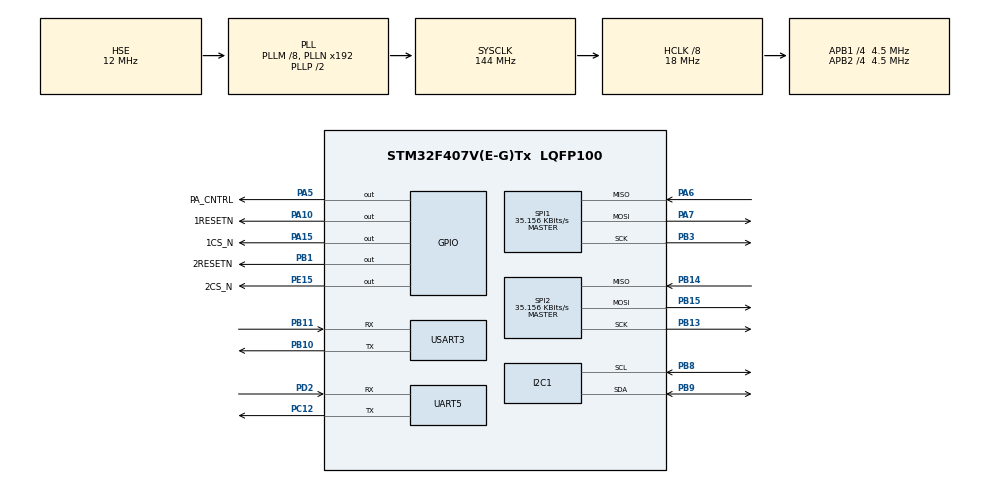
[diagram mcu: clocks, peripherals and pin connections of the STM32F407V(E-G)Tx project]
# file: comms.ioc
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Mcu.Family=STM32F4
Mcu.Name=STM32F407V(E-G)Tx
Mcu.Package=LQFP100
NVIC.PriorityGroup=NVIC_PRIORITYGROUP_4
PA10.GPIO_Label=1RESETN
PA10.PinState=GPIO_PIN_SET
PA10.Signal=GPIO_Output
PA15.GPIO_Label=1CS_N
PA15.PinState=GPIO_PIN_SET
PA15.Signal=GPIO_Output
PA5.GPIO_Label=PA_CNTRL
PA5.Signal=GPIO_Output
PA6.GPIO_Speed=GPIO_SPEED_FREQ_LOW
PA6.Mode=Full_Duplex_Master
PA6.Signal=SPI1_MISO
PA7.GPIO_Speed=GPIO_SPEED_FREQ_LOW
PA7.Mode=Full_Duplex_Master
PA7.Signal=SPI1_MOSI
PB1.GPIO_Label=2RESETN
PB1.PinState=GPIO_PIN_SET
PB1.Signal=GPIO_Output
PB10.Mode=Asynchronous
PB10.Signal=USART3_TX
PB11.Mode=Asynchronous
PB11.Signal=USART3_RX
PB13.GPIO_Speed=GPIO_SPEED_FREQ_LOW
PB13.Mode=Full_Duplex_Master
PB13.Signal=SPI2_SCK
PB14.GPIO_Speed=GPIO_SPEED_FREQ_LOW
PB14.Mode=Full_Duplex_Master
PB14.Signal=SPI2_MISO
PB15.GPIO_Speed=GPIO_SPEED_FREQ_LOW
PB15.Mode=Full_Duplex_Master
PB15.Signal=SPI2_MOSI
PB3.GPIO_Speed=GPIO_SPEED_FREQ_LOW
PB3.Mode=Full_Duplex_Master
PB3.Signal=SPI1_SCK
PB8.Mode=I2C
PB8.Signal=I2C1_SCL
PB9.Mode=I2C
PB9.Signal=I2C1_SDA
PC12.Mode=Asynchronous
PC12.Signal=UART5_TX
PD2.Mode=Asynchronous
PD2.Signal=UART5_RX
PE15.GPIO_Label=2CS_N
PE15.PinState=GPIO_PIN_SET
PE15.Signal=GPIO_Output
PH0-OSC_IN.Mode=HSE-External-Oscillator
PH0-OSC_IN.Signal=RCC_OSC_IN
PH1-OSC_OUT.Mode=HSE-External-Oscillator
PH1-OSC_OUT.Signal=RCC_OSC_OUT
ProjectManager.HeapSize=0x200
ProjectManager.StackSize=0x400
ProjectManager.TargetToolchain=SW4STM32
RCC.48MHZClocksFreq_Value=72000000
RCC.AHBCLKDivider=RCC_SYSCLK_DIV8
RCC.AHBFreq_Value=18000000
RCC.APB1CLKDivider=RCC_HCLK_DIV4
RCC.APB1Freq_Value=4500000
RCC.APB1TimFreq_Value=9000000
RCC.APB2CLKDivider=RCC_HCLK_DIV4
RCC.APB2Freq_Value=4500000
RCC.APB2TimFreq_Value=9000000
RCC.CortexFreq_Value=18000000
RCC.HCLKFreq_Value=18000000
RCC.HSE_VALUE=12000000
RCC.HSI_VALUE=16000000
RCC.LSE_VALUE=32768
RCC.PLLM=8
RCC.PLLSourceVirtual=RCC_PLLSOURCE_HSE
RCC.SYSCLKFreq_VALUE=144000000
RCC.SYSCLKSource=RCC_SYSCLKSOURCE_PLLCLK
RCC.VCOOutputFreq_Value=288000000
SPI1.BaudRatePrescaler=SPI_BAUDRATEPRESCALER_128
SPI1.CalculateBaudRate=35.156 KBits/s
SPI1.Mode=SPI_MODE_MASTER
SPI2.BaudRatePrescaler=SPI_BAUDRATEPRESCALER_128
SPI2.CalculateBaudRate=35.156 KBits/s
SPI2.Mode=SPI_MODE_MASTER
board=comms

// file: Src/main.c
/**
  ******************************************************************************
  * File Name          : main.c
  * Description        : Main program body
  ******************************************************************************
  *
  * COPYRIGHT(c) 2016 STMicroelectronics
  *
  * Redistribution and use in source and binary forms, with or without modification,
  * are permitted provided that the following conditions are met:
  *   1. Redistributions of source code must retain the above copyright notice,
  *      this list of conditions and the following disclaimer.
  *   2. Redistributions in binary form must reproduce the above copyright notice,
  *      this list of conditions and the following disclaimer in the documentation
  *      and/or other materials provided with the distribution.
  *   3. Neither the name of STMicroelectronics nor the names of its contributors
  *      may be used to endorse or promote products derived from this software
  *      without specific prior written permission.
  *
  * THIS SOFTWARE IS PROVIDED BY THE COPYRIGHT HOLDERS AND CONTRIBUTORS "AS IS"
  * AND ANY EXPRESS OR IMPLIED WARRANTIES, INCLUDING, BUT NOT LIMITED TO, THE
  * IMPLIED WARRANTIES OF MERCHANTABILITY AND FITNESS FOR A PARTICULAR PURPOSE ARE
  * DISCLAIMED. IN NO EVENT SHALL THE COPYRIGHT HOLDER OR CONTRIBUTORS BE LIABLE
  * FOR ANY DIRECT, INDIRECT, INCIDENTAL, SPECIAL, EXEMPLARY, OR CONSEQUENTIAL
  * DAMAGES (INCLUDING, BUT NOT LIMITED TO, PROCUREMENT OF SUBSTITUTE GOODS OR
  * SERVICES; LOSS OF USE, DATA, OR PROFITS; OR BUSINESS INTERRUPTION) HOWEVER
  * CAUSED AND ON ANY THEORY OF LIABILITY, WHETHER IN CONTRACT, STRICT LIABILITY,
  * OR TORT (INCLUDING NEGLIGENCE OR OTHERWISE) ARISING IN ANY WAY OUT OF THE USE
  * OF THIS SOFTWARE, EVEN IF ADVISED OF THE POSSIBILITY OF SUCH DAMAGE.
  *
  ******************************************************************************
  */
#include "stm32f4xx_hal.h"

/* USER CODE BEGIN Includes */
#include "../../../../cc1120/cc_definitions.h"
#include "../../../../cc1120/cc_Tx_Init.h"
#include "../../../../cc1120/cc112x_spi.h"
/* USER CODE END Includes */

I2C_HandleTypeDef hi2c1;

SPI_HandleTypeDef hspi1;
SPI_HandleTypeDef hspi2;

UART_HandleTypeDef huart5;
UART_HandleTypeDef huart3;

/* USER CODE BEGIN PV */
/* Private variables ---------------------------------------------------------*/

/* USER CODE END PV */

void SystemClock_Config(void);
static void MX_GPIO_Init(void);
static void MX_I2C1_Init(void);
static void MX_SPI1_Init(void);
static void MX_SPI2_Init(void);
static void MX_UART5_Init(void);
static void MX_USART3_UART_Init(void);

/* USER CODE BEGIN PFP */
/* Private function prototypes -----------------------------------------------*/

/* USER CODE END PFP */

int main(void)
{

  /* MCU Configuration----------------------------------------------------------*/

  /* Reset of all peripherals, Initializes the Flash interface and the Systick. */
  HAL_Init();

  /* Configure the system clock */
  SystemClock_Config();

  /* Initialize all configured peripherals */
  MX_GPIO_Init();
  MX_I2C1_Init();
  MX_SPI1_Init();
  MX_SPI2_Init();
  MX_UART5_Init();
  MX_USART3_UART_Init();

  /* USER CODE BEGIN 2 */
  cc_Tx_INIT();
  /* USER CODE END 2 */

  /* Infinite loop */
  while (1)
  {

  }

}

/** System Clock Configuration
*/
void SystemClock_Config(void)
{

  RCC_OscInitTypeDef RCC_OscInitStruct;
  RCC_ClkInitTypeDef RCC_ClkInitStruct;

  __HAL_RCC_PWR_CLK_ENABLE();

  __HAL_PWR_VOLTAGESCALING_CONFIG(PWR_REGULATOR_VOLTAGE_SCALE1);

  RCC_OscInitStruct.OscillatorType = RCC_OSCILLATORTYPE_HSE;
  RCC_OscInitStruct.HSEState = RCC_HSE_ON;
  RCC_OscInitStruct.PLL.PLLState = RCC_PLL_ON;
  RCC_OscInitStruct.PLL.PLLSource = RCC_PLLSOURCE_HSE;
  RCC_OscInitStruct.PLL.PLLM = 8;
  RCC_OscInitStruct.PLL.PLLN = 192;
  RCC_OscInitStruct.PLL.PLLP = RCC_PLLP_DIV2;
  RCC_OscInitStruct.PLL.PLLQ = 4;
  HAL_RCC_OscConfig(&RCC_OscInitStruct);

  RCC_ClkInitStruct.ClockType = RCC_CLOCKTYPE_HCLK|RCC_CLOCKTYPE_SYSCLK
                              |RCC_CLOCKTYPE_PCLK1|RCC_CLOCKTYPE_PCLK2;
  RCC_ClkInitStruct.SYSCLKSource = RCC_SYSCLKSOURCE_PLLCLK;
  RCC_ClkInitStruct.AHBCLKDivider = RCC_SYSCLK_DIV8;
  RCC_ClkInitStruct.APB1CLKDivider = RCC_HCLK_DIV4;
  RCC_ClkInitStruct.APB2CLKDivider = RCC_HCLK_DIV4;
  HAL_RCC_ClockConfig(&RCC_ClkInitStruct, FLASH_LATENCY_0);

  HAL_SYSTICK_Config(HAL_RCC_GetHCLKFreq()/1000);

  HAL_SYSTICK_CLKSourceConfig(SYSTICK_CLKSOURCE_HCLK);

  /* SysTick_IRQn interrupt configuration */
  HAL_NVIC_SetPriority(SysTick_IRQn, 0, 0);
}

/* I2C1 init function */
void MX_I2C1_Init(void)
{

  hi2c1.Instance = I2C1;
  hi2c1.Init.ClockSpeed = 100000;
  hi2c1.Init.DutyCycle = I2C_DUTYCYCLE_2;
  hi2c1.Init.OwnAddress1 = 0;
  hi2c1.Init.AddressingMode = I2C_ADDRESSINGMODE_7BIT;
  hi2c1.Init.DualAddressMode = I2C_DUALADDRESS_DISABLE;
  hi2c1.Init.OwnAddress2 = 0;
  hi2c1.Init.GeneralCallMode = I2C_GENERALCALL_DISABLE;
  hi2c1.Init.NoStretchMode = I2C_NOSTRETCH_DISABLE;
  HAL_I2C_Init(&hi2c1);

}

/* SPI1 init function */
void MX_SPI1_Init(void)
{

  hspi1.Instance = SPI1;
  hspi1.Init.Mode = SPI_MODE_MASTER;
  hspi1.Init.Direction = SPI_DIRECTION_2LINES;
  hspi1.Init.DataSize = SPI_DATASIZE_8BIT;
  hspi1.Init.CLKPolarity = SPI_POLARITY_LOW;
  hspi1.Init.CLKPhase = SPI_PHASE_1EDGE;
  hspi1.Init.NSS = SPI_NSS_SOFT;
  hspi1.Init.BaudRatePrescaler = SPI_BAUDRATEPRESCALER_128;
  hspi1.Init.FirstBit = SPI_FIRSTBIT_MSB;
  hspi1.Init.TIMode = SPI_TIMODE_DISABLE;
  hspi1.Init.CRCCalculation = SPI_CRCCALCULATION_DISABLE;
  hspi1.Init.CRCPolynomial = 10;
  HAL_SPI_Init(&hspi1);

}

/* SPI2 init function */
void MX_SPI2_Init(void)
{

  hspi2.Instance = SPI2;
  hspi2.Init.Mode = SPI_MODE_MASTER;
  hspi2.Init.Direction = SPI_DIRECTION_2LINES;
  hspi2.Init.DataSize = SPI_DATASIZE_8BIT;
  hspi2.Init.CLKPolarity = SPI_POLARITY_LOW;
  hspi2.Init.CLKPhase = SPI_PHASE_1EDGE;
  hspi2.Init.NSS = SPI_NSS_SOFT;
  hspi2.Init.BaudRatePrescaler = SPI_BAUDRATEPRESCALER_128;
  hspi2.Init.FirstBit = SPI_FIRSTBIT_MSB;
  hspi2.Init.TIMode = SPI_TIMODE_DISABLE;
  hspi2.Init.CRCCalculation = SPI_CRCCALCULATION_DISABLE;
  hspi2.Init.CRCPolynomial = 10;
  HAL_SPI_Init(&hspi2);

}

/* UART5 init function */
void MX_UART5_Init(void)
{

  huart5.Instance = UART5;
  huart5.Init.BaudRate = 115200;
  huart5.Init.WordLength = UART_WORDLENGTH_8B;
  huart5.Init.StopBits = UART_STOPBITS_1;
  huart5.Init.Parity = UART_PARITY_NONE;
  huart5.Init.Mode = UART_MODE_TX_RX;
  huart5.Init.HwFlowCtl = UART_HWCONTROL_NONE;
  huart5.Init.OverSampling = UART_OVERSAMPLING_16;
  HAL_UART_Init(&huart5);

}

/* USART3 init function */
void MX_USART3_UART_Init(void)
{

  huart3.Instance = USART3;
  huart3.Init.BaudRate = 115200;
  huart3.Init.WordLength = UART_WORDLENGTH_8B;
  huart3.Init.StopBits = UART_STOPBITS_1;
  huart3.Init.Parity = UART_PARITY_NONE;
  huart3.Init.Mode = UART_MODE_TX_RX;
  huart3.Init.HwFlowCtl = UART_HWCONTROL_NONE;
  huart3.Init.OverSampling = UART_OVERSAMPLING_16;
  HAL_UART_Init(&huart3);

}

/** Configure pins as
        * Analog
        * Input
        * Output
        * EVENT_OUT
        * EXTI
*/
void MX_GPIO_Init(void)
{

  GPIO_InitTypeDef GPIO_InitStruct;

  /* GPIO Ports Clock Enable */
  __HAL_RCC_GPIOH_CLK_ENABLE();
  __HAL_RCC_GPIOA_CLK_ENABLE();
  __HAL_RCC_GPIOB_CLK_ENABLE();
  __HAL_RCC_GPIOE_CLK_ENABLE();
  __HAL_RCC_GPIOC_CLK_ENABLE();
  __HAL_RCC_GPIOD_CLK_ENABLE();

  /*Configure GPIO pin Output Level */
  HAL_GPIO_WritePin(PA_CNTRL_GPIO_Port, PA_CNTRL_Pin, GPIO_PIN_RESET);

  /*Configure GPIO pin Output Level */
  HAL_GPIO_WritePin(RESETN_RX_GPIO_Port, RESETN_RX_Pin, GPIO_PIN_SET);

  /*Configure GPIO pin Output Level */
  HAL_GPIO_WritePin(CS_SPI2_RX_GPIO_Port, CS_SPI2_RX_Pin, GPIO_PIN_SET);

  /*Configure GPIO pin Output Level */
  HAL_GPIO_WritePin(GPIOA, RESETN_TX_Pin|CS_SPI1_TX_Pin, GPIO_PIN_SET);

  /*Configure GPIO pins : PA_CNTRL_Pin RESETN_TX_Pin CS_SPI1_TX_Pin */
  GPIO_InitStruct.Pin = PA_CNTRL_Pin|RESETN_TX_Pin|CS_SPI1_TX_Pin;
  GPIO_InitStruct.Mode = GPIO_MODE_OUTPUT_PP;
  GPIO_InitStruct.Pull = GPIO_NOPULL;
  GPIO_InitStruct.Speed = GPIO_SPEED_FREQ_LOW;
  HAL_GPIO_Init(GPIOA, &GPIO_InitStruct);

  /*Configure GPIO pin : RESETN_RX_Pin */
  GPIO_InitStruct.Pin = RESETN_RX_Pin;
  GPIO_InitStruct.Mode = GPIO_MODE_OUTPUT_PP;
  GPIO_InitStruct.Pull = GPIO_NOPULL;
  GPIO_InitStruct.Speed = GPIO_SPEED_FREQ_LOW;
  HAL_GPIO_Init(RESETN_RX_GPIO_Port, &GPIO_InitStruct);

  /*Configure GPIO pin : CS_SPI2_RX_Pin */
  GPIO_InitStruct.Pin = CS_SPI2_RX_Pin;
  GPIO_InitStruct.Mode = GPIO_MODE_OUTPUT_PP;
  GPIO_InitStruct.Pull = GPIO_NOPULL;
  GPIO_InitStruct.Speed = GPIO_SPEED_FREQ_LOW;
  HAL_GPIO_Init(CS_SPI2_RX_GPIO_Port, &GPIO_InitStruct);

}

/************************ (C) COPYRIGHT STMicroelectronics *****END OF FILE****/
